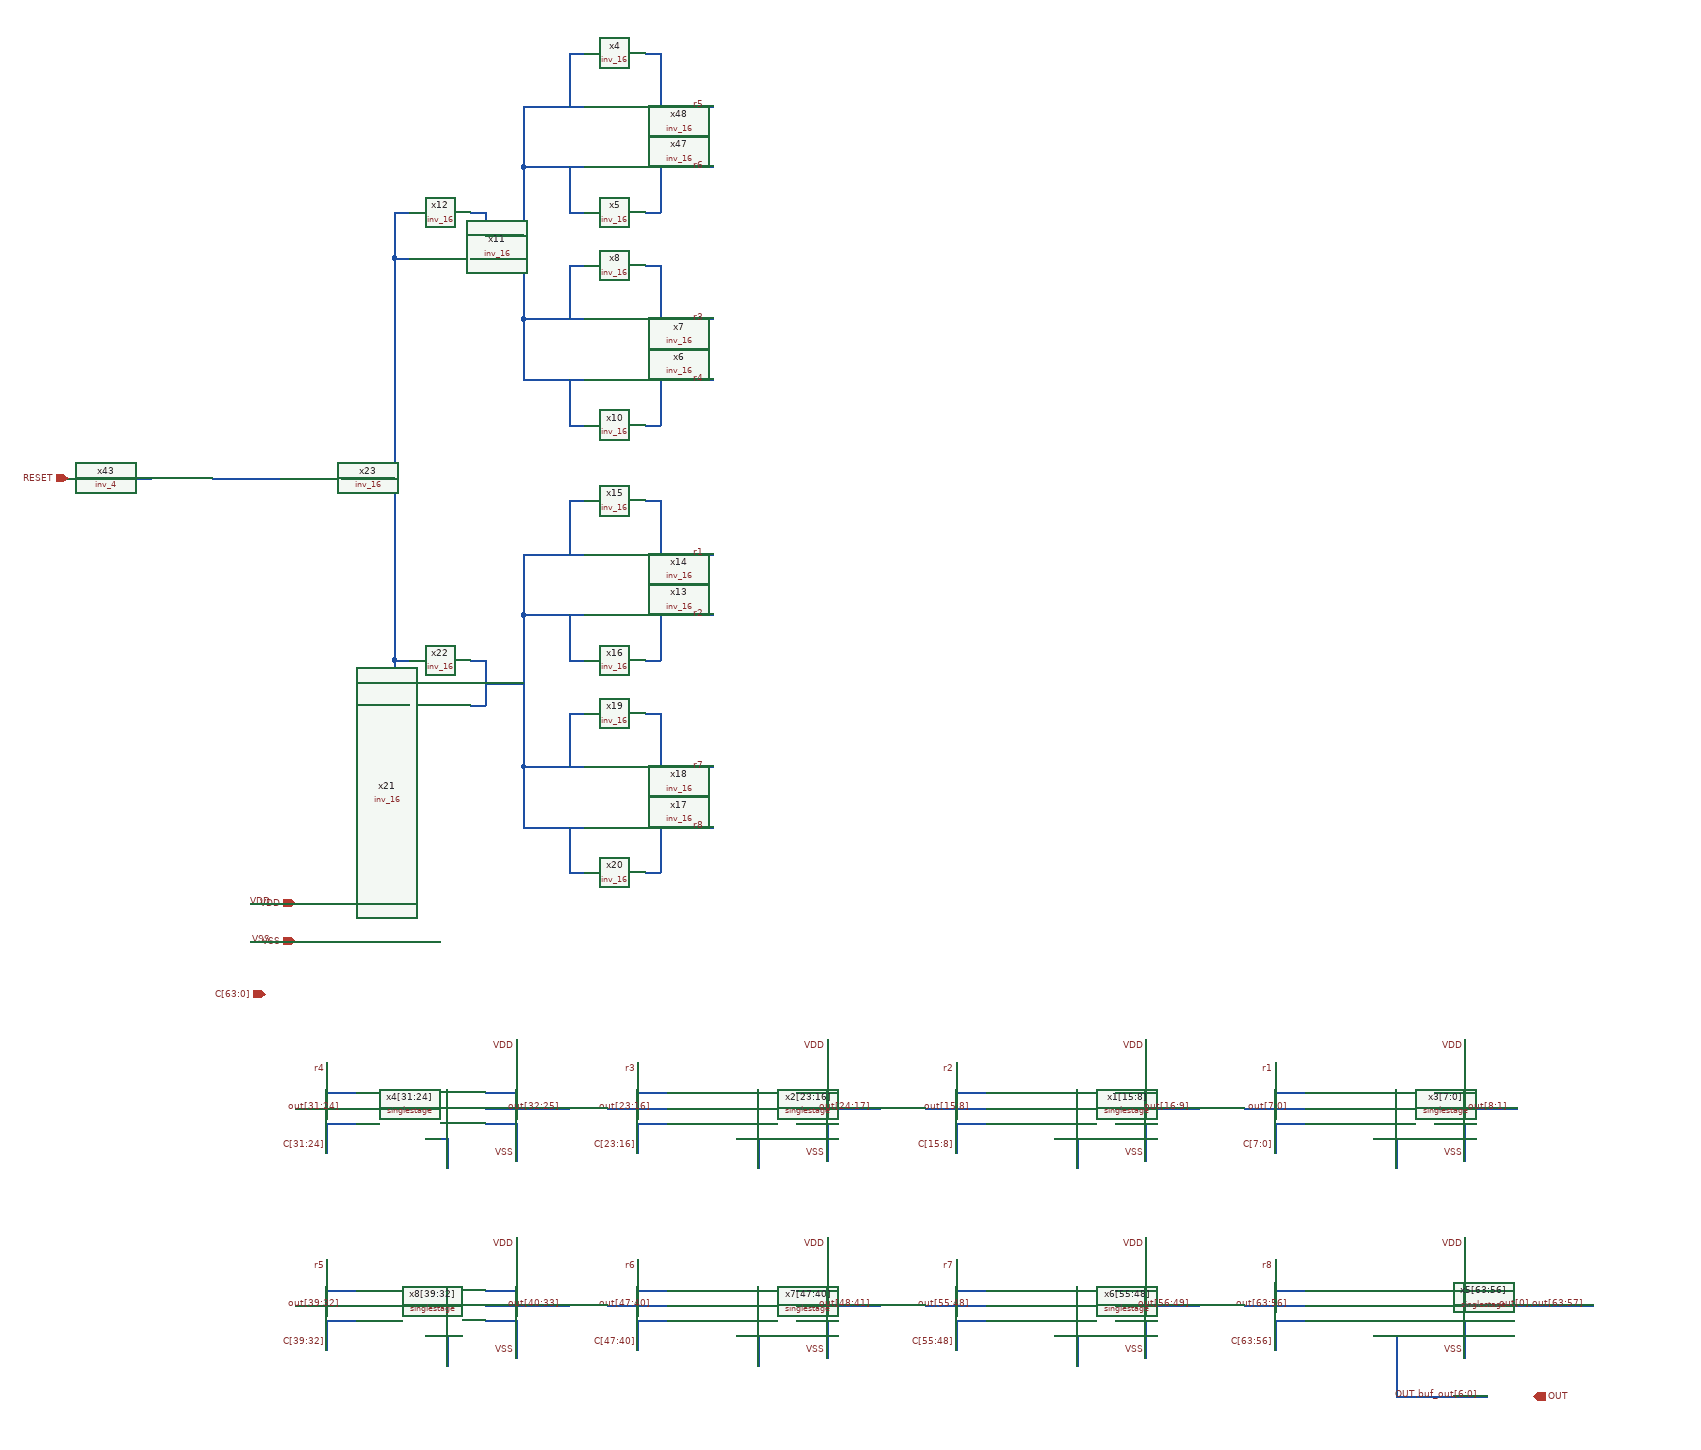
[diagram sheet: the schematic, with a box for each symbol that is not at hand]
v {xschem version=3.0.0 file_version=1.2 }
G {}
K {}
V {}
S {}
E {}
N -170 -340 -100 -340 { lab=VDD}
N -170 -290 -100 -290 { lab=VSS}
N 190 -1390 190 -1330 { lab=#net1}
N 190 -1390 270 -1390 { lab=#net1}
N 190 -1330 190 -1310 { lab=#net1}
N 190 -1310 270 -1310 { lab=#net1}
N 350 -1390 400 -1390 { lab=r5}
N 350 -1310 390 -1310 { lab=r6}
N -360 -900 -300 -900 { lab=RESET}
N -420 -900 -360 -900 { lab=RESET}
N 350 -1460 370 -1460 { lab=r5}
N 370 -1460 370 -1390 { lab=r5}
N 250 -1460 270 -1460 { lab=#net1}
N 250 -1460 250 -1390 { lab=#net1}
N 400 -1390 430 -1390 { lab=r5}
N 430 -1390 440 -1390 { lab=r5}
N 390 -1310 440 -1310 { lab=r6}
N 250 -1250 270 -1250 { lab=#net1}
N 250 -1310 250 -1250 { lab=#net1}
N 350 -1250 370 -1250 { lab=r6}
N 370 -1310 370 -1250 { lab=r6}
N 190 -1110 190 -1050 { lab=#net1}
N 190 -1110 270 -1110 { lab=#net1}
N 190 -1050 190 -1030 { lab=#net1}
N 190 -1030 270 -1030 { lab=#net1}
N 350 -1110 400 -1110 { lab=r3}
N 350 -1030 390 -1030 { lab=r4}
N 350 -1180 370 -1180 { lab=r3}
N 370 -1180 370 -1110 { lab=r3}
N 250 -1180 270 -1180 { lab=#net1}
N 250 -1180 250 -1110 { lab=#net1}
N 400 -1110 430 -1110 { lab=r3}
N 430 -1110 440 -1110 { lab=r3}
N 390 -1030 440 -1030 { lab=r4}
N 250 -970 270 -970 { lab=#net1}
N 250 -1030 250 -970 { lab=#net1}
N 350 -970 370 -970 { lab=r4}
N 370 -1030 370 -970 { lab=r4}
N 190 -1310 190 -1110 { lab=#net1}
N 120 -1250 140 -1250 { lab=#net1}
N 140 -1250 140 -1190 { lab=#net1}
N 120 -1190 140 -1190 { lab=#net1}
N 20 -1190 40 -1190 { lab=#net2}
N 20 -1250 20 -1190 { lab=#net2}
N 20 -1250 40 -1250 { lab=#net2}
N 140 -1220 190 -1220 { lab=#net1}
N 190 -800 190 -740 { lab=#net3}
N 190 -800 270 -800 { lab=#net3}
N 190 -740 190 -720 { lab=#net3}
N 190 -720 270 -720 { lab=#net3}
N 350 -800 400 -800 { lab=r1}
N 350 -720 390 -720 { lab=r2}
N 350 -870 370 -870 { lab=r1}
N 370 -870 370 -800 { lab=r1}
N 250 -870 270 -870 { lab=#net3}
N 250 -870 250 -800 { lab=#net3}
N 400 -800 430 -800 { lab=r1}
N 430 -800 440 -800 { lab=r1}
N 390 -720 440 -720 { lab=r2}
N 250 -660 270 -660 { lab=#net3}
N 250 -720 250 -660 { lab=#net3}
N 350 -660 370 -660 { lab=r2}
N 370 -720 370 -660 { lab=r2}
N 190 -520 190 -460 { lab=#net3}
N 190 -520 270 -520 { lab=#net3}
N 190 -460 190 -440 { lab=#net3}
N 190 -440 270 -440 { lab=#net3}
N 350 -520 400 -520 { lab=r7}
N 350 -440 390 -440 { lab=r8}
N 350 -590 370 -590 { lab=r7}
N 370 -590 370 -520 { lab=r7}
N 250 -590 270 -590 { lab=#net3}
N 250 -590 250 -520 { lab=#net3}
N 400 -520 430 -520 { lab=r7}
N 430 -520 440 -520 { lab=r7}
N 390 -440 440 -440 { lab=r8}
N 250 -380 270 -380 { lab=#net3}
N 250 -440 250 -380 { lab=#net3}
N 350 -380 370 -380 { lab=r8}
N 370 -440 370 -380 { lab=r8}
N 190 -720 190 -520 { lab=#net3}
N 120 -660 140 -660 { lab=#net3}
N 140 -660 140 -600 { lab=#net3}
N 120 -600 140 -600 { lab=#net3}
N 20 -600 40 -600 { lab=#net2}
N 20 -660 20 -600 { lab=#net2}
N 20 -660 40 -660 { lab=#net2}
N 140 -630 190 -630 { lab=#net3}
N 20 -1190 20 -660 { lab=#net2}
N -50 -900 20 -900 { lab=#net2}
N -220 -900 -130 -900 { lab=#net4}
N 1390 -70 1460 -70 { lab=out[8:1]}
N 1390 -90 1430 -90 { lab=VDD}
N 1430 -130 1430 -90 { lab=VDD}
N 1390 -50 1430 -50 { lab=VSS}
N 1430 -50 1430 -20 { lab=VSS}
N 1310 -30 1340 -30 { lab=#net5}
N 1340 -30 1340 10 { lab=#net5}
N 1180 -90 1220 -90 { lab=r1}
N 1180 -70 1220 -70 { lab=out[7:0]}
N 1180 -50 1220 -50 { lab=C[7:0]}
N 1430 -160 1430 -130 { lab=VDD}
N 1430 -20 1430 0 { lab=VSS}
N 1460 -70 1500 -70 { lab=out[8:1]}
N 1140 -70 1180 -70 { lab=out[7:0]}
N 1180 -50 1180 -10 { lab=C[7:0]}
N 1180 -130 1180 -90 { lab=r1}
N 970 -70 1040 -70 { lab=out[16:9]}
N 970 -90 1010 -90 { lab=VDD}
N 1010 -130 1010 -90 { lab=VDD}
N 970 -50 1010 -50 { lab=VSS}
N 1010 -50 1010 -20 { lab=VSS}
N 890 -30 920 -30 { lab=#net6}
N 920 -30 920 10 { lab=#net6}
N 760 -90 800 -90 { lab=r2}
N 760 -70 800 -70 { lab=out[15:8]}
N 760 -50 800 -50 { lab=C[15:8]}
N 1010 -160 1010 -130 { lab=VDD}
N 1010 -20 1010 0 { lab=VSS}
N 1040 -70 1080 -70 { lab=out[16:9]}
N 720 -70 760 -70 { lab=out[15:8]}
N 760 -50 760 -10 { lab=C[15:8]}
N 760 -130 760 -90 { lab=r2}
N 550 -70 620 -70 { lab=out[24:17]}
N 550 -90 590 -90 { lab=VDD}
N 590 -130 590 -90 { lab=VDD}
N 550 -50 590 -50 { lab=VSS}
N 590 -50 590 -20 { lab=VSS}
N 470 -30 500 -30 { lab=#net7}
N 500 -30 500 10 { lab=#net7}
N 340 -90 380 -90 { lab=r3}
N 340 -70 380 -70 { lab=out[23:16]}
N 340 -50 380 -50 { lab=C[23:16]}
N 590 -160 590 -130 { lab=VDD}
N 590 -20 590 0 { lab=VSS}
N 620 -70 660 -70 { lab=out[24:17]}
N 300 -70 340 -70 { lab=out[23:16]}
N 340 -50 340 -10 { lab=C[23:16]}
N 340 -130 340 -90 { lab=r3}
N 140 -70 210 -70 { lab=out[32:25]}
N 140 -90 180 -90 { lab=VDD}
N 180 -130 180 -90 { lab=VDD}
N 140 -50 180 -50 { lab=VSS}
N 180 -50 180 -20 { lab=VSS}
N 60 -30 90 -30 { lab=#net8}
N 90 -30 90 10 { lab=#net8}
N -70 -90 -30 -90 { lab=r4}
N -70 -70 -30 -70 { lab=out[31:24]}
N -70 -50 -30 -50 { lab=C[31:24]}
N 180 -160 180 -130 { lab=VDD}
N 180 -20 180 0 { lab=VSS}
N 210 -70 250 -70 { lab=out[32:25]}
N -110 -70 -70 -70 { lab=out[31:24]}
N -70 -50 -70 -10 { lab=C[31:24]}
N -70 -130 -70 -90 { lab=r4}
N 1390 190 1460 190 { lab=out[0],out[63:57]}
N 1390 170 1430 170 { lab=VDD}
N 1430 130 1430 170 { lab=VDD}
N 1390 210 1430 210 { lab=VSS}
N 1430 210 1430 240 { lab=VSS}
N 1310 230 1340 230 { lab=OUT,buf_out[6:0]}
N 1340 230 1340 270 { lab=OUT,buf_out[6:0]}
N 1180 170 1220 170 { lab=r8}
N 1180 190 1220 190 { lab=out[63:56]}
N 1180 210 1220 210 { lab=C[63:56]}
N 1430 100 1430 130 { lab=VDD}
N 1430 240 1430 260 { lab=VSS}
N 1460 190 1500 190 { lab=out[0],out[63:57]}
N 1140 190 1180 190 { lab=out[63:56]}
N 1180 210 1180 250 { lab=C[63:56]}
N 1180 130 1180 170 { lab=r8}
N 970 190 1040 190 { lab=out[56:49]}
N 970 170 1010 170 { lab=VDD}
N 1010 130 1010 170 { lab=VDD}
N 970 210 1010 210 { lab=VSS}
N 1010 210 1010 240 { lab=VSS}
N 890 230 920 230 { lab=#net9}
N 920 230 920 270 { lab=#net9}
N 760 170 800 170 { lab=r7}
N 760 190 800 190 { lab=out[55:48]}
N 760 210 800 210 { lab=C[55:48]}
N 1010 100 1010 130 { lab=VDD}
N 1010 240 1010 260 { lab=VSS}
N 1040 190 1080 190 { lab=out[56:49]}
N 720 190 760 190 { lab=out[55:48]}
N 760 210 760 250 { lab=C[55:48]}
N 760 130 760 170 { lab=r7}
N 550 190 620 190 { lab=out[48:41]}
N 550 170 590 170 { lab=VDD}
N 590 130 590 170 { lab=VDD}
N 550 210 590 210 { lab=VSS}
N 590 210 590 240 { lab=VSS}
N 470 230 500 230 { lab=#net10}
N 500 230 500 270 { lab=#net10}
N 340 170 380 170 { lab=r6}
N 340 190 380 190 { lab=out[47:40]}
N 340 210 380 210 { lab=C[47:40]}
N 590 100 590 130 { lab=VDD}
N 590 240 590 260 { lab=VSS}
N 620 190 660 190 { lab=out[48:41]}
N 300 190 340 190 { lab=out[47:40]}
N 340 210 340 250 { lab=C[47:40]}
N 340 130 340 170 { lab=r6}
N 140 190 210 190 { lab=out[40:33]}
N 140 170 180 170 { lab=VDD}
N 180 130 180 170 { lab=VDD}
N 140 210 180 210 { lab=VSS}
N 180 210 180 240 { lab=VSS}
N 60 230 90 230 { lab=#net11}
N 90 230 90 270 { lab=#net11}
N -70 170 -30 170 { lab=r5}
N -70 190 -30 190 { lab=out[39:32]}
N -70 210 -30 210 { lab=C[39:32]}
N 180 100 180 130 { lab=VDD}
N 180 240 180 260 { lab=VSS}
N 210 190 250 190 { lab=out[40:33]}
N -110 190 -70 190 { lab=out[39:32]}
N -70 210 -70 250 { lab=C[39:32]}
N -70 130 -70 170 { lab=r5}
N 1500 190 1600 190 { lab=out[0],out[63:57]}
N 1340 270 1340 310 { lab=OUT,buf_out[6:0]}
N 1340 310 1460 310 { lab=OUT,buf_out[6:0]}
C {devices/iopin.sym} -110 -340 0 0 {name=p1 lab=VDD}
C {devices/lab_pin.sym} -140 -340 0 0 {name=l23 sig_type=std_logic lab=VDD}
C {devices/iopin.sym} -110 -290 0 0 {name=p2 lab=VSS}
C {devices/lab_pin.sym} -140 -290 0 0 {name=l27 sig_type=std_logic lab=VSS}
C {devices/opin.sym} 1520 310 0 0 {name=p3 lab=OUT}
C {sky130_stdcells/inv_4.sym} -260 -900 0 0 {name=x43 VGND=VSS VNB=VSS VPB=VDD VPWR=VDD prefix=sky130_fd_sc_hd__ }
C {sky130_stdcells/inv_16.sym} 310 -1310 0 0 {name=x47 VGND=VSS VNB=VSS VPB=VDD VPWR=VDD prefix=sky130_fd_sc_hd__ }
C {sky130_stdcells/inv_16.sym} 310 -1390 0 0 {name=x48 VGND=VSS VNB=VSS VPB=VDD VPWR=VDD prefix=sky130_fd_sc_hd__ }
C {devices/lab_pin.sym} 430 -1390 0 0 {name=l3 sig_type=std_logic lab=r5}
C {devices/lab_pin.sym} 430 -1310 0 0 {name=l4 sig_type=std_logic lab=r6}
C {devices/ipin.sym} -150 -220 0 0 {name=p28 lab=C[63:0]}
C {devices/ipin.sym} -410 -900 0 0 {name=p36 lab=RESET}
C {sky130_stdcells/inv_16.sym} 310 -1460 0 0 {name=x4 VGND=VSS VNB=VSS VPB=VDD VPWR=VDD prefix=sky130_fd_sc_hd__ }
C {sky130_stdcells/inv_16.sym} 310 -1250 0 0 {name=x5 VGND=VSS VNB=VSS VPB=VDD VPWR=VDD prefix=sky130_fd_sc_hd__ }
C {sky130_stdcells/inv_16.sym} 310 -1030 0 0 {name=x6 VGND=VSS VNB=VSS VPB=VDD VPWR=VDD prefix=sky130_fd_sc_hd__ }
C {sky130_stdcells/inv_16.sym} 310 -1110 0 0 {name=x7 VGND=VSS VNB=VSS VPB=VDD VPWR=VDD prefix=sky130_fd_sc_hd__ }
C {devices/lab_pin.sym} 430 -1110 0 0 {name=l2 sig_type=std_logic lab=r3}
C {devices/lab_pin.sym} 430 -1030 0 0 {name=l7 sig_type=std_logic lab=r4}
C {sky130_stdcells/inv_16.sym} 310 -1180 0 0 {name=x8 VGND=VSS VNB=VSS VPB=VDD VPWR=VDD prefix=sky130_fd_sc_hd__ }
C {sky130_stdcells/inv_16.sym} 310 -970 0 0 {name=x10 VGND=VSS VNB=VSS VPB=VDD VPWR=VDD prefix=sky130_fd_sc_hd__ }
C {sky130_stdcells/inv_16.sym} 80 -1190 0 0 {name=x11 VGND=VSS VNB=VSS VPB=VDD VPWR=VDD prefix=sky130_fd_sc_hd__ }
C {sky130_stdcells/inv_16.sym} 80 -1250 0 0 {name=x12 VGND=VSS VNB=VSS VPB=VDD VPWR=VDD prefix=sky130_fd_sc_hd__ }
C {sky130_stdcells/inv_16.sym} 310 -720 0 0 {name=x13 VGND=VSS VNB=VSS VPB=VDD VPWR=VDD prefix=sky130_fd_sc_hd__ }
C {sky130_stdcells/inv_16.sym} 310 -800 0 0 {name=x14 VGND=VSS VNB=VSS VPB=VDD VPWR=VDD prefix=sky130_fd_sc_hd__ }
C {devices/lab_pin.sym} 430 -800 0 0 {name=l8 sig_type=std_logic lab=r1}
C {devices/lab_pin.sym} 430 -720 0 0 {name=l9 sig_type=std_logic lab=r2}
C {sky130_stdcells/inv_16.sym} 310 -870 0 0 {name=x15 VGND=VSS VNB=VSS VPB=VDD VPWR=VDD prefix=sky130_fd_sc_hd__ }
C {sky130_stdcells/inv_16.sym} 310 -660 0 0 {name=x16 VGND=VSS VNB=VSS VPB=VDD VPWR=VDD prefix=sky130_fd_sc_hd__ }
C {sky130_stdcells/inv_16.sym} 310 -440 0 0 {name=x17 VGND=VSS VNB=VSS VPB=VDD VPWR=VDD prefix=sky130_fd_sc_hd__ }
C {sky130_stdcells/inv_16.sym} 310 -520 0 0 {name=x18 VGND=VSS VNB=VSS VPB=VDD VPWR=VDD prefix=sky130_fd_sc_hd__ }
C {devices/lab_pin.sym} 430 -520 0 0 {name=l11 sig_type=std_logic lab=r7}
C {devices/lab_pin.sym} 430 -440 0 0 {name=l12 sig_type=std_logic lab=r8}
C {sky130_stdcells/inv_16.sym} 310 -590 0 0 {name=x19 VGND=VSS VNB=VSS VPB=VDD VPWR=VDD prefix=sky130_fd_sc_hd__ }
C {sky130_stdcells/inv_16.sym} 310 -380 0 0 {name=x20 VGND=VSS VNB=VSS VPB=VDD VPWR=VDD prefix=sky130_fd_sc_hd__ }
C {sky130_stdcells/inv_16.sym} 80 -600 0 0 {name=x21 VGND=VSS VNB=VSS VPB=VDD VPWR=VDD prefix=sky130_fd_sc_hd__ }
C {sky130_stdcells/inv_16.sym} 80 -660 0 0 {name=x22 VGND=VSS VNB=VSS VPB=VDD VPWR=VDD prefix=sky130_fd_sc_hd__ }
C {sky130_stdcells/inv_16.sym} -90 -900 0 0 {name=x23 VGND=VSS VNB=VSS VPB=VDD VPWR=VDD prefix=sky130_fd_sc_hd__ }
C {singlestage.sym} 1370 -70 0 0 {name=x3[7:0]}
C {devices/lab_pin.sym} 1430 -150 0 0 {name=l1 sig_type=std_logic lab=VDD}
C {devices/lab_pin.sym} 1430 -10 0 0 {name=l5 sig_type=std_logic lab=VSS}
C {devices/lab_pin.sym} 1490 -70 0 0 {name=l6 sig_type=std_logic lab=out[8:1]}
C {devices/lab_pin.sym} 1200 -70 0 0 {name=l10 sig_type=std_logic lab=out[7:0]}
C {devices/lab_pin.sym} 1180 -20 0 0 {name=l13 sig_type=std_logic lab=C[7:0]}
C {devices/lab_pin.sym} 1180 -120 0 0 {name=l14 sig_type=std_logic lab=r1}
C {singlestage.sym} 950 -70 0 0 {name=x1[15:8]}
C {devices/lab_pin.sym} 1010 -150 0 0 {name=l15 sig_type=std_logic lab=VDD}
C {devices/lab_pin.sym} 1010 -10 0 0 {name=l16 sig_type=std_logic lab=VSS}
C {devices/lab_pin.sym} 1070 -70 0 0 {name=l17 sig_type=std_logic lab=out[16:9]}
C {devices/lab_pin.sym} 780 -70 0 0 {name=l18 sig_type=std_logic lab=out[15:8]}
C {devices/lab_pin.sym} 760 -20 0 0 {name=l19 sig_type=std_logic lab=C[15:8]}
C {devices/lab_pin.sym} 760 -120 0 0 {name=l20 sig_type=std_logic lab=r2}
C {singlestage.sym} 530 -70 0 0 {name=x2[23:16]}
C {devices/lab_pin.sym} 590 -150 0 0 {name=l21 sig_type=std_logic lab=VDD}
C {devices/lab_pin.sym} 590 -10 0 0 {name=l22 sig_type=std_logic lab=VSS}
C {devices/lab_pin.sym} 650 -70 0 0 {name=l24 sig_type=std_logic lab=out[24:17]}
C {devices/lab_pin.sym} 360 -70 0 0 {name=l25 sig_type=std_logic lab=out[23:16]}
C {devices/lab_pin.sym} 340 -20 0 0 {name=l26 sig_type=std_logic lab=C[23:16]}
C {devices/lab_pin.sym} 340 -120 0 0 {name=l28 sig_type=std_logic lab=r3}
C {singlestage.sym} 120 -70 0 0 {name=x4[31:24]}
C {devices/lab_pin.sym} 180 -150 0 0 {name=l29 sig_type=std_logic lab=VDD}
C {devices/lab_pin.sym} 180 -10 0 0 {name=l30 sig_type=std_logic lab=VSS}
C {devices/lab_pin.sym} 240 -70 0 0 {name=l31 sig_type=std_logic lab=out[32:25]}
C {devices/lab_pin.sym} -50 -70 0 0 {name=l32 sig_type=std_logic lab=out[31:24]}
C {devices/lab_pin.sym} -70 -20 0 0 {name=l33 sig_type=std_logic lab=C[31:24]}
C {devices/lab_pin.sym} -70 -120 0 0 {name=l34 sig_type=std_logic lab=r4}
C {singlestage.sym} 1370 190 0 0 {name=x5[63:56]}
C {devices/lab_pin.sym} 1430 110 0 0 {name=l35 sig_type=std_logic lab=VDD}
C {devices/lab_pin.sym} 1430 250 0 0 {name=l36 sig_type=std_logic lab=VSS}
C {devices/lab_pin.sym} 1590 190 0 0 {name=l37 sig_type=std_logic lab=out[0],out[63:57]}
C {devices/lab_pin.sym} 1200 190 0 0 {name=l38 sig_type=std_logic lab=out[63:56]}
C {devices/lab_pin.sym} 1180 240 0 0 {name=l39 sig_type=std_logic lab=C[63:56]}
C {devices/lab_pin.sym} 1180 140 0 0 {name=l40 sig_type=std_logic lab=r8}
C {singlestage.sym} 950 190 0 0 {name=x6[55:48]}
C {devices/lab_pin.sym} 1010 110 0 0 {name=l41 sig_type=std_logic lab=VDD}
C {devices/lab_pin.sym} 1010 250 0 0 {name=l42 sig_type=std_logic lab=VSS}
C {devices/lab_pin.sym} 1070 190 0 0 {name=l43 sig_type=std_logic lab=out[56:49]}
C {devices/lab_pin.sym} 780 190 0 0 {name=l44 sig_type=std_logic lab=out[55:48]}
C {devices/lab_pin.sym} 760 240 0 0 {name=l45 sig_type=std_logic lab=C[55:48]}
C {devices/lab_pin.sym} 760 140 0 0 {name=l46 sig_type=std_logic lab=r7}
C {singlestage.sym} 530 190 0 0 {name=x7[47:40]}
C {devices/lab_pin.sym} 590 110 0 0 {name=l79 sig_type=std_logic lab=VDD}
C {devices/lab_pin.sym} 590 250 0 0 {name=l80 sig_type=std_logic lab=VSS}
C {devices/lab_pin.sym} 650 190 0 0 {name=l81 sig_type=std_logic lab=out[48:41]}
C {devices/lab_pin.sym} 360 190 0 0 {name=l82 sig_type=std_logic lab=out[47:40]}
C {devices/lab_pin.sym} 340 240 0 0 {name=l83 sig_type=std_logic lab=C[47:40]}
C {devices/lab_pin.sym} 340 140 0 0 {name=l84 sig_type=std_logic lab=r6}
C {singlestage.sym} 120 190 0 0 {name=x8[39:32]}
C {devices/lab_pin.sym} 180 110 0 0 {name=l85 sig_type=std_logic lab=VDD}
C {devices/lab_pin.sym} 180 250 0 0 {name=l86 sig_type=std_logic lab=VSS}
C {devices/lab_pin.sym} 240 190 0 0 {name=l87 sig_type=std_logic lab=out[40:33]}
C {devices/lab_pin.sym} -50 190 0 0 {name=l88 sig_type=std_logic lab=out[39:32]}
C {devices/lab_pin.sym} -70 240 0 0 {name=l89 sig_type=std_logic lab=C[39:32]}
C {devices/lab_pin.sym} -70 140 0 0 {name=l90 sig_type=std_logic lab=r5}
C {devices/lab_pin.sym} 1450 310 0 0 {name=l98 sig_type=std_logic lab=OUT,buf_out[6:0]}
